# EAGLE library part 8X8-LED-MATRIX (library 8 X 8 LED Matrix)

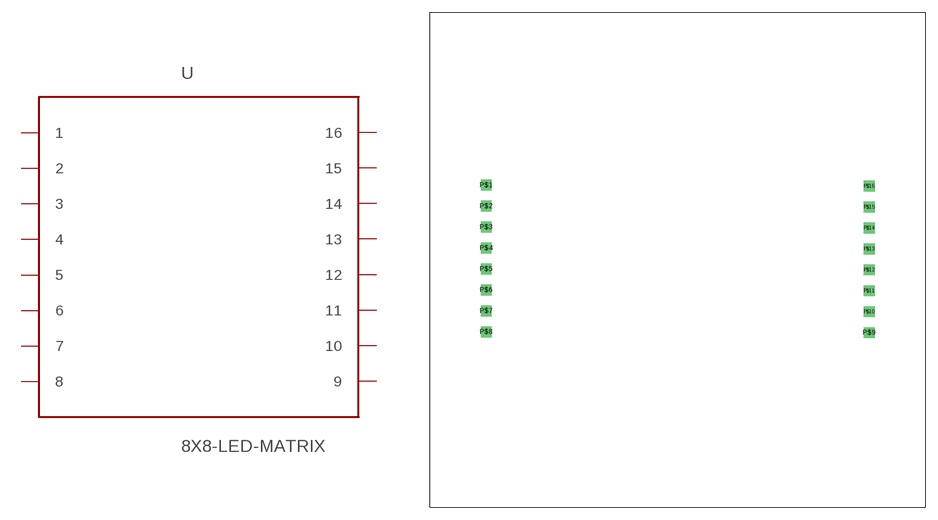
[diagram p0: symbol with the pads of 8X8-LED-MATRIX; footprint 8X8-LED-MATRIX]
Designator prefix -

## 8X8-LED-MATRIX  [8X8-LED-MATRIX]
P$1  1
P$2  2
P$3  3
P$4  4
P$5  5
P$6  6
P$7  7
P$8  8
P$9  9
P$10  10
P$11  11
P$12  12
P$13  13
P$14  14
P$15  15
P$16  16

## Footprint 8X8-LED-MATRIX (pad centres in mm)
8 x 8 LED Matrix Row Anode
drill 0.8 square: P$1 -23.2,9.04; P$2 -23.2,6.5; P$3 -23.2,3.96; P$4 -23.2,1.42; P$5 -23.2,-1.12; P$6 -23.2,-3.66; P$7 -23.2,-6.2; P$8 -23.2,-8.74; P$9 23.23,-8.84; P$10 23.23,-6.3; P$11 23.23,-3.76; P$12 23.23,-1.22; P$13 23.23,1.32; P$14 23.23,3.86; P$15 23.23,6.4; P$16 23.23,8.94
